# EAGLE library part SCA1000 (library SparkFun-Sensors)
Dual 4g accelerometer, SPI and analog out

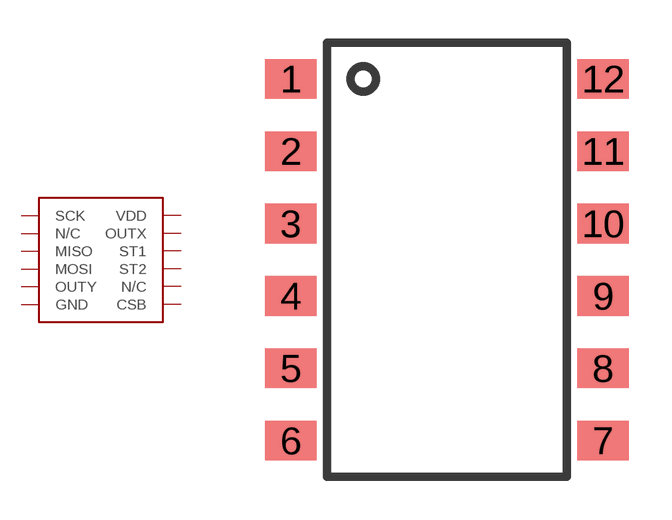
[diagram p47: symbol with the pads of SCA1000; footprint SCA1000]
Designator prefix -

## SCA1000  [SCA1000]
1  SCK
2  N/C
3  MISO
4  MOSI
5  OUTY
6  GND
7  CSB
8  N/C
9  ST2
10  ST1
11  OUTX
12  VDD

## Footprint SCA1000 (pad centres in mm)
smd 1.81 x 1.39: 1 0,0; 2 0,-2.54; 3 0,-5.08; 4 0,-7.62; 5 0,-10.16; 6 0,-12.7; 7 10.96,-12.7; 8 10.96,-10.16; 9 10.96,-7.62; 10 10.96,-5.08; 11 10.96,-2.54; 12 10.96,0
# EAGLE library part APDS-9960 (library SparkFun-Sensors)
Avago APDS-9960 digital proximity, ambient light, RGB, and gesture sensor.

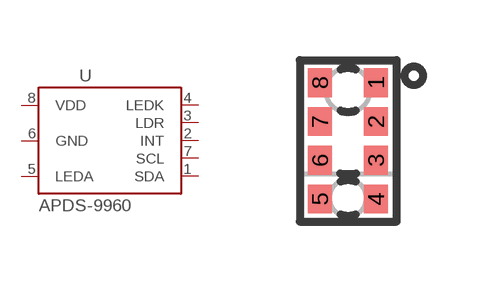
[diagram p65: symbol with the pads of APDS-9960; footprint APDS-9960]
Designator prefix U

## APDS-9960 (PROD_ID: SEN-12005)  [APDS-9960]
1  SDA
2  INT
3  LDR
4  LEDK
5  LEDA
6  GND
7  SCL
8  VDD

## Footprint APDS-9960 (pad centres in mm)
smd 0.6 x 0.72: 1 0.7,1.455; 2 0.7,0.485; 3 0.7,-0.485; 4 0.7,-1.455; 5 -0.7,-1.455; 6 -0.7,-0.485; 7 -0.7,0.485; 8 -0.7,1.455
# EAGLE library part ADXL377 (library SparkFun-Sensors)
ADXL377 Low Power 3-Axis ±200 g Accelerometer with Analog Output.

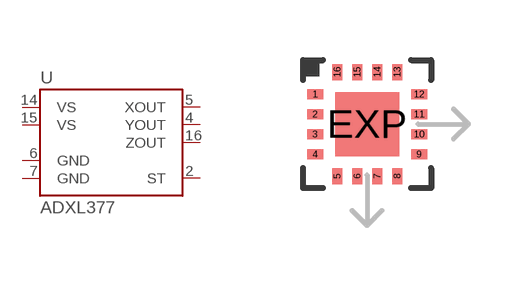
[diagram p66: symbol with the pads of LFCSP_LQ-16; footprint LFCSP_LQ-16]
Designator prefix -

## ADXL377  [LFCSP_LQ-16]
2  ST
4  YOUT
5  XOUT
6  GND
7  GND
14  VS
15  VS
16  ZOUT

## Footprint LFCSP_LQ-16 (pad centres in mm)
smd 0.4 x 0.25: 1 -1.3,0.75; 2 -1.3,0.25; 3 -1.3,-0.25; 4 -1.3,-0.75; 9 1.3,-0.75; 10 1.3,-0.25; 11 1.3,0.25; 12 1.3,0.75
smd 0.25 x 0.4: 5 -0.75,-1.3; 6 -0.25,-1.3; 7 0.25,-1.3; 8 0.75,-1.3; 13 0.75,1.3; 14 0.25,1.3; 15 -0.25,1.3; 16 -0.75,1.3
smd 1.6 x 1.6: EXP 0,0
